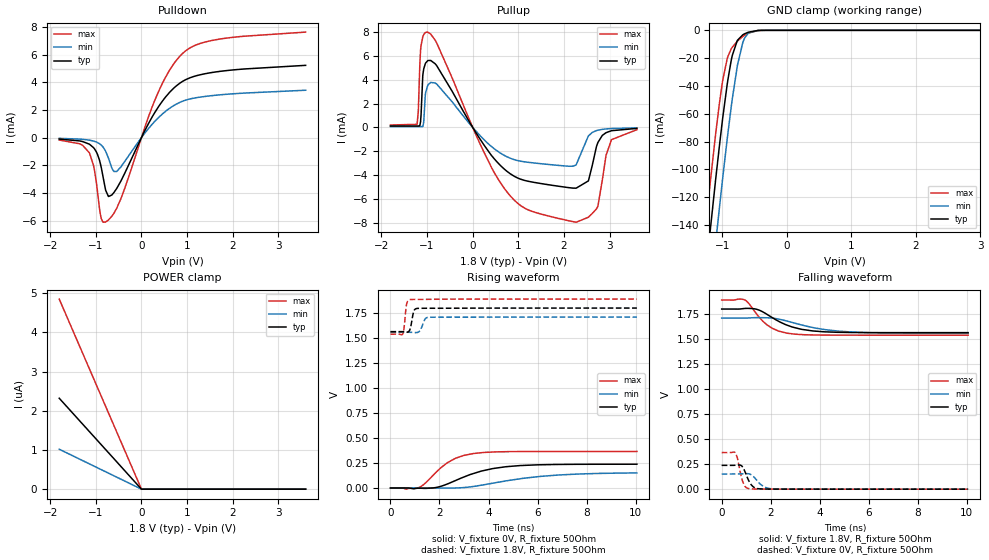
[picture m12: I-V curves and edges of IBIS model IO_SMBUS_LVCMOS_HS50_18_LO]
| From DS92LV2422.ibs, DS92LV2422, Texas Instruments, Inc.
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|   IO_SMBUS_LVCMOS_18_LO
[Model]   IO_SMBUS_LVCMOS_HS50_18_LO
Model_type   I/O
Polarity   Non-Inverting
Enable   Active-Low
Vinl = 0.63
Vinh = 1.17
Vmeas = 1.65
Vref = 1.65
Cref = 15pF
Rref = 50
|   typ   min   max
C_comp   0.7659pF   0.7659pF   0.7659pF
[Voltage Range]   1.8   1.71   1.89
[Temperature Range]   25   105   -40
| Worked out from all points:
|   slope of the pulldown table from 0 to 0.27 V, typ, clamps not added: 159 ohm
|   slope of the pullup table from 0 to 0.27 V, typ, clamps not added: 169 ohm
|   GND clamp passes 1 mA (typ) near -0.55 V on its own axis
|   falling waveform, V_fixture 1.8V, R_fixture 50Ohm: 20-80 % time 1.22ns typ, 1.76ns min, 833ps max; typ from 1.8 V to 1.56 V
|   rising waveform, V_fixture 0V, R_fixture 50Ohm: 20-80 % time 1.71ns typ, 2.6ns min, 1.09ns max; typ from 0 V to 0.238 V
|   rising waveform, V_fixture 1.8V, R_fixture 50Ohm: 20-80 % time 109ps typ, 148ps min, 87.1ps max; typ from 1.56 V to 1.8 V
|   falling waveform, V_fixture 0V, R_fixture 50Ohm: 20-80 % time 274ps typ, 373ps min, 206ps max; typ from 0.238 V to 0 V
[Pulldown]
|   Voltage   I(typ)   I(min)   I(max)
-1.8V     -105.7uA   -54.09uA   -174uA
-1.141V   -472.6uA   -183.4uA   -1.093mA
-1.028V   -813.9uA   -270.1uA   -2.37mA
-876.6mV  -2.214mA   -550.9uA   -5.887mA
-784.8mV  -3.795mA   -977.1uA   -6.109mA
-720mV    -4.257mA   -1.508mA   -5.944mA
-541.8mV  -3.68mA    -2.452mA   -5.111mA
306mV     1.89mA     1.222mA    2.806mA
608.4mV   3.247mA    2.103mA    4.837mA
910.8mV   4.087mA    2.646mA    6.118mA
1.667V    4.769mA    3.078mA    7.102mA
3.595V    5.227mA    3.427mA    7.633mA
[GND Clamp]
|   Voltage   I(typ)   I(min)   I(max)
-1.8V     -432.2mA   -478.5mA   -397.7mA
-1.255V   -174.4mA   -221.2mA   -139.5mA
-1.19V    -145.3mA   -191.7mA   -110.9mA
-1.103V   -107.6mA   -153.3mA   -74.75mA
-1.044V   -82.96mA   -127.5mA   -52.43mA
-990mV    -61.92mA   -104.8mA   -35.27mA
-925.2mV  -39.37mA   -78.79mA   -20.71mA
-865.8mV  -22.74mA   -56.64mA   -13.72mA
-763.2mV  -7.086mA   -24.77mA   -7.683mA
-655.2mV  -2.529mA   -5.716mA   -3.512mA
-428.4mV  -69.59uA   -66.07uA   -127.6uA
3.595V    0A         0A         0A
[Pullup]
|   Voltage   I(typ)   I(min)   I(max)
-1.8V     115.4uA    67.11uA    199.7uA
-1.217V   114.4uA    66.53uA    258.7uA
-1.13V    1.031mA    66.52uA    6.879mA
-1.087V   4.531mA    108.7uA    7.661mA
-1.033V   5.38mA     2.819mA    7.981mA
-979.2mV  5.62mA     3.566mA    8.007mA
754.2mV   -3.705mA   -2.476mA   -5.439mA
2.266V    -5.107mA   -3.136mA   -7.971mA
2.531V    -4.504mA   -735.8uA   -7.557mA
2.736V    -1.319mA   -241uA     -6.665mA
3.038V    -278.8uA   -97.48uA   -1.03mA
3.595V    -85.52uA   -40.93uA   -192.5uA
[POWER Clamp]
|   Voltage   I(typ)   I(min)   I(max)
-1.8V     2.321uA    1.019uA    4.851uA
0V        0A         0A         0A
3.595V    0A         0A         0A
[Ramp]
R_load = 50
|   typ   min   max
dV/dt_r   0.142842/1.70529e-09  0.0906507/2.60497e-09   0.219399/1.09365e-09
dV/dt_f   0.141587/1.21826e-09  0.0911941/1.75889e-09   0.210703/8.33397e-10
[Falling Waveform]
V_fixture = 1.8V
V_fixture_min = 1.71V
V_fixture_max = 1.89V
R_fixture = 50Ohm
C_fixture = 0F
|   Time   V(typ)   V(min)   V(max)
0s        1.8V       1.71V      1.89V
944.3ps   1.806V     1.71V      1.89V
1.119ns   1.806V     1.711V     1.851V
1.455ns   1.795V     1.714V     1.741V
1.851ns   1.746V     1.713V     1.641V
2.331ns   1.676V     1.699V     1.579V
2.659ns   1.64V      1.68V      1.559V
3.706ns   1.581V     1.616V     1.541V
4.774ns   1.567V     1.579V     1.539V
10.05ns   1.564V     1.558V     1.539V
[Rising Waveform]
V_fixture = 0V
V_fixture_min = 0V
V_fixture_max = 0V
R_fixture = 50Ohm
C_fixture = 0F
|   Time   V(typ)   V(min)   V(max)
0s        1.304uV    2.687uV    999.1nV
653.1ps   162.6uV    120.5uV    -11.54mV
1.18ns    -1.471mV   -734uV     6.737mV
1.888ns   6.156mV    -661.5uV   164.1mV
2.331ns   41.39mV    -379.1uV   254.6mV
3.382ns   144.7mV    15.61mV    344.9mV
4.185ns   195mV      48.8mV     360.1mV
5.298ns   224.7mV    92.82mV    364.8mV
6.865ns   235.7mV    130.3mV    365.6mV
10.05ns   238.1mV    151.1mV    365.7mV
[Rising Waveform]
V_fixture = 1.8V
V_fixture_min = 1.71V
V_fixture_max = 1.89V
R_fixture = 50Ohm
C_fixture = 0F
|   Time   V(typ)   V(min)   V(max)
0s        1.564V     1.558V     1.539V
488.9ps   1.564V     1.558V     1.536V
545.6ps   1.563V     1.558V     1.583V
653.1ps   1.56V      1.558V     1.832V
810.9ps   1.599V     1.557V     1.885V
944.2ps   1.764V     1.556V     1.887V
1.118ns   1.797V     1.557V     1.887V
1.41ns    1.798V     1.691V     1.887V
1.554ns   1.798V     1.708V     1.887V
10.05ns   1.8V       1.71V      1.89V
[Falling Waveform]
|Gnd
V_fixture = 0V
V_fixture_min = 0V
V_fixture_max = 0V
R_fixture = 50Ohm
C_fixture = 0F
|   Time   V(typ)   V(min)   V(max)
0s        238.1mV    151mV      365.7mV
577.1ps   239.3mV    151.8mV    356.7mV
653.1ps   240.9mV    152mV      297.6mV
789.2ps   237.5mV    152.7mV    136.1mV
902.2ps   200.7mV    153.9mV    48.07mV
1.119ns   77.47mV    152.6mV    5.2mV
1.379ns   10.45mV    103.7mV    1.325mV
1.734ns   1.647mV    23.74mV    662.4uV
2.083ns   687.8uV    2.963mV    417.1uV
10.05ns   1.313uV    2.523uV    1.275uV
